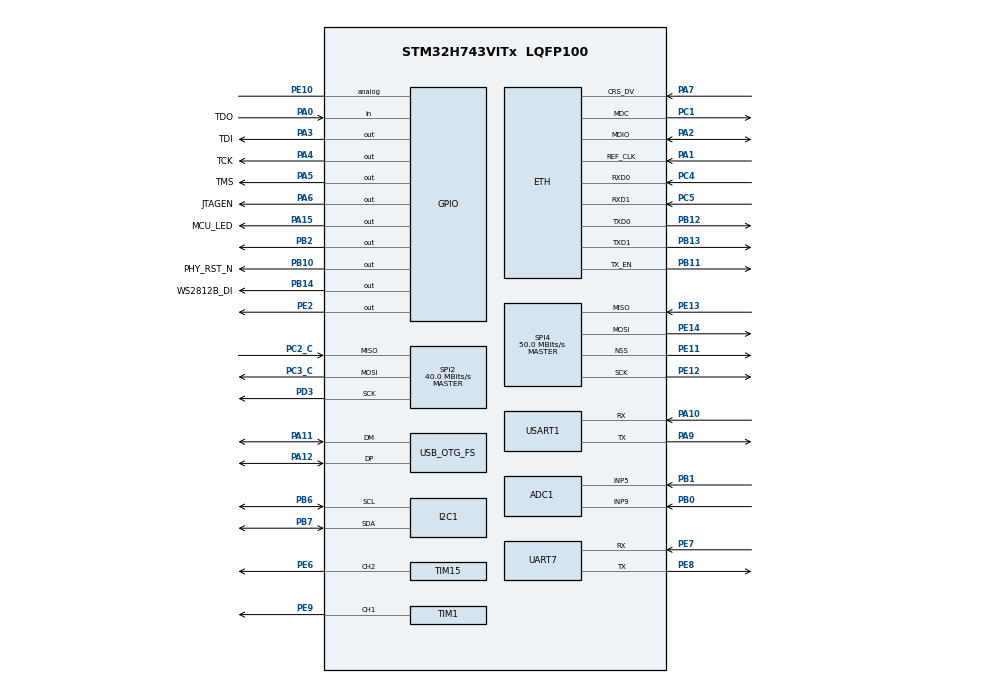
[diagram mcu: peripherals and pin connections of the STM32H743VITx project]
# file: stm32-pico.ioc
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ADC1.Channel-1\#ChannelRegularConversion=ADC_CHANNEL_5
ADC1.OversamplingMode=ENABLE
ADC1.Rank-1\#ChannelRegularConversion=1
ADC1.Ratio=10
ADC1.SamplingTime-1\#ChannelRegularConversion=ADC_SAMPLETIME_64CYCLES_5
ADC1.master=1
CORTEX_M7.AccessPermission-Cortex_Memory_Protection_Unit_Region0_Settings=MPU_REGION_FULL_ACCESS
CORTEX_M7.AccessPermission-Cortex_Memory_Protection_Unit_Region1_Settings=MPU_REGION_FULL_ACCESS
CORTEX_M7.BaseAddress-Cortex_Memory_Protection_Unit_Region0_Settings=0x30000000
CORTEX_M7.BaseAddress-Cortex_Memory_Protection_Unit_Region1_Settings=0x30000000
CORTEX_M7.CPU_DCache=Enabled
CORTEX_M7.CPU_ICache=Enabled
CORTEX_M7.DisableExec-Cortex_Memory_Protection_Unit_Region0_Settings=MPU_INSTRUCTION_ACCESS_DISABLE
CORTEX_M7.DisableExec-Cortex_Memory_Protection_Unit_Region1_Settings=MPU_INSTRUCTION_ACCESS_DISABLE
CORTEX_M7.Enable-Cortex_Memory_Protection_Unit_Region0_Settings=MPU_REGION_ENABLE
CORTEX_M7.Enable-Cortex_Memory_Protection_Unit_Region1_Settings=MPU_REGION_ENABLE
CORTEX_M7.IsBufferable-Cortex_Memory_Protection_Unit_Region1_Settings=MPU_ACCESS_BUFFERABLE
CORTEX_M7.IsShareable-Cortex_Memory_Protection_Unit_Region1_Settings=MPU_ACCESS_SHAREABLE
CORTEX_M7.MPU_Control=MPU_PRIVILEGED_DEFAULT
CORTEX_M7.Size-Cortex_Memory_Protection_Unit_Region0_Settings=MPU_REGION_SIZE_32KB
CORTEX_M7.Size-Cortex_Memory_Protection_Unit_Region1_Settings=MPU_REGION_SIZE_512B
CORTEX_M7.TypeExtField-Cortex_Memory_Protection_Unit_Region0_Settings=MPU_TEX_LEVEL1
ETH.MediaInterface=HAL_ETH_RMII_MODE
ETH.RxBuffLen=1536
ETH.RxDescAddress=0x30000000
ETH.TxDescAddress=0x30000060
FREERTOS.Tasks01=defaultTask,24,256,StartDefaultTask,Default,NULL,Dynamic,NULL,NULL
FREERTOS.configMINIMAL_STACK_SIZE=256
FREERTOS.configUSE_NEWLIB_REENTRANT=1
I2C1.Timing=0x10C0ECFF
IWDG1.Prescaler=IWDG_PRESCALER_32
LWIP.BSP.number=1
LWIP.DEFAULT_THREAD_PRIO=48
LWIP.GATEWAY_ADDRESS=192.168.031.001
LWIP.IP_ADDRESS=192.168.031.100
LWIP.LWIP_DHCP=0
LWIP.LWIP_RAM_HEAP_POINTER=0x30004000
LWIP.NETMASK_ADDRESS=255.255.255.000
LWIP.PBUF_POOL_BUFSIZE=1500
LWIP.TCP_MSS=1426
LWIP.TCP_WND=5704
LWIP.Version=v2.1.2_Cube
LWIP0.BSP.STBoard=false
LWIP0.BSP.api=BSP_COMPONENT_DRIVER
LWIP0.BSP.component=LAN8742
LWIP0.BSP.i2caddr=0
LWIP0.BSP.instance=LAN8742
LWIP0.BSP.name=Driver_PHY
LWIP0.BSP.solution=LAN8742
Mcu.Family=STM32H7
Mcu.Name=STM32H743VITx
Mcu.Package=LQFP100
NVIC.ETH_IRQn=true\:5\:0\:false\:false\:true\:true\:true\:true
NVIC.OTG_FS_IRQn=true\:5\:0\:false\:false\:true\:true\:true\:true
NVIC.PriorityGroup=NVIC_PRIORITYGROUP_4
NVIC.TIM2_IRQn=true\:15\:0\:false\:false\:true\:false\:false\:true
NVIC.TimeBase=TIM2_IRQn
NVIC.TimeBaseIP=TIM2
PA0.GPIO_Label=TDO
PA0.Signal=GPIO_Input
PA1.GPIO_Speed=GPIO_SPEED_FREQ_VERY_HIGH
PA1.Mode=RMII
PA1.Signal=ETH_REF_CLK
PA10.Mode=Asynchronous
PA10.Signal=USART1_RX
PA11.GPIO_Speed=GPIO_SPEED_FREQ_HIGH
PA11.Mode=Device_Only
PA11.Signal=USB_OTG_FS_DM
PA12.GPIO_Speed=GPIO_SPEED_FREQ_HIGH
PA12.Mode=Device_Only
PA12.Signal=USB_OTG_FS_DP
PA13\ (JTMS/SWDIO).Mode=Serial_Wire
PA13\ (JTMS/SWDIO).Signal=DEBUG_JTMS-SWDIO
PA14\ (JTCK/SWCLK).Mode=Serial_Wire
PA14\ (JTCK/SWCLK).Signal=DEBUG_JTCK-SWCLK
PA15\ (JTDI).GPIO_Label=MCU_LED
PA15\ (JTDI).Signal=GPIO_Output
PA2.GPIO_Speed=GPIO_SPEED_FREQ_VERY_HIGH
PA2.Mode=RMII
PA2.Signal=ETH_MDIO
PA3.GPIO_Label=TDI
PA3.GPIO_Speed=GPIO_SPEED_FREQ_HIGH
PA3.Signal=GPIO_Output
PA4.GPIO_Label=TCK
PA4.GPIO_Speed=GPIO_SPEED_FREQ_HIGH
PA4.Signal=GPIO_Output
PA5.GPIO_Label=TMS
PA5.Signal=GPIO_Output
PA6.GPIO_Label=JTAGEN
PA6.GPIO_Speed=GPIO_SPEED_FREQ_HIGH
PA6.Signal=GPIO_Output
PA7.GPIO_Speed=GPIO_SPEED_FREQ_VERY_HIGH
PA7.Mode=RMII
PA7.Signal=ETH_CRS_DV
PA9.Mode=Asynchronous
PA9.Signal=USART1_TX
PB0.Signal=ADCx_INP9
PB1.Signal=ADCx_INP5
PB10.GPIO_Label=PHY_RST_N
PB10.GPIO_PuPd=GPIO_PULLDOWN
PB10.Signal=GPIO_Output
PB11.GPIO_Speed=GPIO_SPEED_FREQ_VERY_HIGH
PB11.Mode=RMII
PB11.Signal=ETH_TX_EN
PB12.GPIO_Speed=GPIO_SPEED_FREQ_VERY_HIGH
PB12.Mode=RMII
PB12.Signal=ETH_TXD0
PB13.GPIO_Speed=GPIO_SPEED_FREQ_VERY_HIGH
PB13.Mode=RMII
PB13.Signal=ETH_TXD1
PB14.GPIO_Label=WS2812B_DI
PB14.GPIO_Speed=GPIO_SPEED_FREQ_HIGH
PB14.Signal=GPIO_Output
PB2.Signal=GPIO_Output
PB6.Mode=I2C
PB6.Signal=I2C1_SCL
PB7.Mode=I2C
PB7.Signal=I2C1_SDA
PC1.GPIO_Speed=GPIO_SPEED_FREQ_VERY_HIGH
PC1.Mode=RMII
PC1.Signal=ETH_MDC
PC2_C.Mode=Full_Duplex_Master
PC2_C.Signal=SPI2_MISO
PC3_C.Mode=Full_Duplex_Master
PC3_C.Signal=SPI2_MOSI
PC4.GPIO_Speed=GPIO_SPEED_FREQ_VERY_HIGH
PC4.Mode=RMII
PC4.Signal=ETH_RXD0
PC5.GPIO_Speed=GPIO_SPEED_FREQ_VERY_HIGH
PC5.Mode=RMII
PC5.Signal=ETH_RXD1
PD3.Mode=Full_Duplex_Master
PD3.Signal=SPI2_SCK
PE10.Signal=GPIO_Analog
PE11.Mode=NSS_Signal_Hard_Output
PE11.Signal=SPI4_NSS
PE12.Mode=Full_Duplex_Master
PE12.Signal=SPI4_SCK
PE13.Mode=Full_Duplex_Master
PE13.Signal=SPI4_MISO
PE14.Mode=Full_Duplex_Master
PE14.Signal=SPI4_MOSI
PE2.Signal=GPIO_Output
PE6.Signal=S_TIM15_CH2
PE7.Mode=Asynchronous
PE7.Signal=UART7_RX
PE8.Mode=Asynchronous
PE8.Signal=UART7_TX
PE9.Signal=S_TIM1_CH1
PH0-OSC_IN\ (PH0).Mode=HSE-External-Oscillator
PH0-OSC_IN\ (PH0).Signal=RCC_OSC_IN
PH1-OSC_OUT\ (PH1).Mode=HSE-External-Oscillator
PH1-OSC_OUT\ (PH1).Signal=RCC_OSC_OUT
ProjectManager.HeapSize=0x200
ProjectManager.StackSize=0x400
ProjectManager.TargetToolchain=STM32CubeIDE
RCC.ADCFreq_Value=80000000
RCC.APB1Freq_Value=100000000
RCC.APB2Freq_Value=100000000
RCC.APB3Freq_Value=100000000
RCC.APB4Freq_Value=100000000
RCC.CortexFreq_Value=400000000
RCC.D1PPRE=RCC_APB3_DIV2
RCC.D2PPRE1=RCC_APB1_DIV2
RCC.D2PPRE2=RCC_APB2_DIV2
RCC.D3PPRE=RCC_APB4_DIV2
RCC.DIVM1=2
RCC.DIVM2=2
RCC.DIVN1=50
RCC.DIVN2=50
RCC.DIVP2=10
RCC.DIVQ1=10
RCC.HCLKFreq_Value=200000000
RCC.HPRE=RCC_HCLK_DIV2
RCC.HSIDiv=RCC_PLLSAIDIVR_2
RCC.PLLSourceVirtual=RCC_PLLSOURCE_HSI
RCC.SYSCLKFreq_VALUE=400000000
RCC.SYSCLKSource=RCC_SYSCLKSOURCE_PLLCLK
RCC.USBCLockSelection=RCC_USBCLKSOURCE_HSI48
RCC.USBFreq_Value=48000000
SH.ADCx_INP5.0=ADC1_INP5,IN5-Single-Ended
SH.ADCx_INP9.0=ADC1_INP9,IN9-Single-Ended
SH.S_TIM15_CH2.0=TIM15_CH2,PWM Generation2 CH2
SH.S_TIM1_CH1.0=TIM1_CH1,PWM Generation1 CH1
SPI2.BaudRatePrescaler=SPI_BAUDRATEPRESCALER_2
SPI2.CalculateBaudRate=40.0 MBits/s
SPI2.Direction=SPI_DIRECTION_2LINES
SPI2.Mode=SPI_MODE_MASTER
SPI2.VirtualType=VM_MASTER
SPI4.CalculateBaudRate=50.0 MBits/s
SPI4.Direction=SPI_DIRECTION_2LINES
SPI4.Mode=SPI_MODE_MASTER
SPI4.VirtualNSS=VM_NSSHARD
SPI4.VirtualType=VM_MASTER
TIM1.Channel-PWM\ Generation1\ CH1=TIM_CHANNEL_1
TIM15.Channel-PWM\ Generation2\ CH2=TIM_CHANNEL_2
USART1.VirtualMode-Asynchronous=VM_ASYNC
USB_OTG_FS.VirtualMode=Device_Only
VP_FREERTOS_VS_CMSIS_V2.Mode=CMSIS_V2
VP_IWDG1_VS_IWDG.Mode=IWDG_Activate
VP_LWIP_VS_Enabled.Mode=Enabled
VP_SYS_VS_tim2.Mode=TIM2
VP_TIM1_VS_ClockSourceINT.Mode=Internal
VP_TIM1_VS_ClockSourceITR.Mode=TriggerSource_ITR0
VP_TIM1_VS_ControllerModeReset.Mode=Reset Mode
VREF+.Mode=InternalMode
VREF+.Signal=VREFBUF_OUT
VREFBUF.VoltageScaling=SYSCFG_VREFBUF_VOLTAGE_SCALE1
board=custom

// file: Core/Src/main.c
/* USER CODE BEGIN Header */
/**
  ******************************************************************************
  * @file           : main.c
  * @brief          : Main program body
  ******************************************************************************
  * @attention
  *
  * Copyright (c) 2024 STMicroelectronics.
  * All rights reserved.
  *
  * This software is licensed under terms that can be found in the LICENSE file
  * in the root directory of this software component.
  * If no LICENSE file comes with this software, it is provided AS-IS.
  *
  ******************************************************************************
  */

/**
 * Sector 0     0x08000000-0x0801FFFF Boot 128KB
 * Sector 1     0x08020000-0x0803FFFF Boot Address, 4B
 * Sector 2-7   0x08040000-0x080FFFFF APP1 768KB
 * Sector 8-3   0x08100000-0x081BFFFF APP2 768KB
 * Sector 14-15 0x081C0000-0x081FFFFF Data 256KB
 */
/* USER CODE END Header */
#include "main.h"
#include "cmsis_os.h"
#include "lwip.h"

/* USER CODE BEGIN Includes */
#include <ctype.h>
#include "bsp/board_api.h"
#include "tusb.h"
#include "usb_stdio.h"
#include "console.h"
#include "pico_cli.h"
#include "pico_reg.h"
/* USER CODE END Includes */

ADC_HandleTypeDef hadc1;

I2C_HandleTypeDef hi2c1;

IWDG_HandleTypeDef hiwdg1;

SPI_HandleTypeDef hspi2;
SPI_HandleTypeDef hspi4;

TIM_HandleTypeDef htim1;
TIM_HandleTypeDef htim15;

UART_HandleTypeDef huart7;
UART_HandleTypeDef huart1;

PCD_HandleTypeDef hpcd_USB_OTG_FS;

/* Definitions for defaultTask */
osThreadId_t defaultTaskHandle;
const osThreadAttr_t defaultTask_attributes = {
  .name = "defaultTask",
  .stack_size = 256 * 4,
  .priority = (osPriority_t) osPriorityNormal,
};
/* USER CODE BEGIN PV */
static int g_heat_led_gap = 500;

osThreadId_t usbTaskHandle;
const osThreadAttr_t usbTask_attributes = {
  .name = "usbTask",
  .stack_size = 256 * 4,
  .priority = (osPriority_t) osPriorityRealtime,
};

osThreadId_t cliTaskHandle;
const osThreadAttr_t cliTask_attributes = {
  .name = "cliTask",
  .stack_size = 256 * 4,
  .priority = (osPriority_t) osPriorityNormal,
};

osThreadId_t iwdgTaskHandle;
const osThreadAttr_t iwdgTask_attributes = {
  .name = "iwdgTask",
  .stack_size = 256,
  .priority = (osPriority_t) osPriorityNormal,
};

uint64_t get_tick_ms()
{
  return (uint64_t)HAL_GetTick();
}

/* USER CODE END PV */

void SystemClock_Config(void);
static void MPU_Config(void);
static void MX_GPIO_Init(void);
static void MX_USB_OTG_FS_PCD_Init(void);
static void MX_SPI2_Init(void);
static void MX_I2C1_Init(void);
static void MX_UART7_Init(void);
static void MX_USART1_UART_Init(void);
static void MX_ADC1_Init(void);
static void MX_TIM1_Init(void);
static void MX_TIM15_Init(void);
static void MX_IWDG1_Init(void);
static void MX_SPI4_Init(void);
void StartDefaultTask(void *argument);

/* USER CODE BEGIN PFP */
typedef void (*pApp)(void);
/* USER CODE END PFP */

/* USER CODE BEGIN 0 */
uint32_t CODE_START_ADDRESS = FLASH_START_ADDRESS;

/**
 * 关于IWDG
 * 使用LSI作为时钟源，LSI是32KHz
 */

/* USER CODE END 0 */

int main(void)
{
  /* USER CODE BEGIN 1 */
  // const uint32_t bootflag = 0x12345678;
  // uint32_t ptr = (uint32_t)(&bootflag);
  // if (ptr < APP_BOOT_ADDRESS_PHY_ADDR) {
  //   CODE_START_ADDRESS = FLASH_START_ADDRESS;
  // }
  // if (ptr > APP1_SECTOR_ADDRESS && ptr < APP2_SECTOR_ADDRESS) {
  //   CODE_START_ADDRESS = APP1_SECTOR_ADDRESS;
  //   SCB->VTOR = APP1_SECTOR_ADDRESS;
  // }
  // if (ptr > APP2_SECTOR_ADDRESS && ptr < DATA_SECTOR_ADDRESS) {
  //   CODE_START_ADDRESS = APP2_SECTOR_ADDRESS;
  //   SCB->VTOR = APP2_SECTOR_ADDRESS;
  // }
  // if (CODE_START_ADDRESS == FLASH_START_ADDRESS) { // bootloader app
  //   const uint32_t APPLICATION_ADDRESS = (*(__IO uint32_t *)APP_BOOT_ADDRESS_PHY_ADDR);
  //   if (APPLICATION_ADDRESS == APP1_SECTOR_ADDRESS || APPLICATION_ADDRESS == APP2_SECTOR_ADDRESS) {
  //     const uint32_t JumpAddress = *(__IO uint32_t *)(APPLICATION_ADDRESS + 4);
  //     pApp JumpToApp = (pApp)JumpAddress;
  //     /* Reconfigure vector table offset register to match the application location */
  //     SCB->VTOR = JumpAddress;
  //     /* Initialize user application's Stack Pointer */
  //     __set_MSP(*(__IO uint32_t *)APPLICATION_ADDRESS);

  //     JumpToApp();
  //     while (1)
  //       ;
  //   }
  // }
  SCB->VTOR = APP1_SECTOR_ADDRESS;
  /* USER CODE END 1 */

  /* MPU Configuration--------------------------------------------------------*/
  MPU_Config();

  /* Enable I-Cache---------------------------------------------------------*/
  SCB_EnableICache();

  /* Enable D-Cache---------------------------------------------------------*/
  SCB_EnableDCache();

  /* MCU Configuration--------------------------------------------------------*/

  /* Reset of all peripherals, Initializes the Flash interface and the Systick. */
  HAL_Init();

  /* Configure the system clock */
  SystemClock_Config();

  /* Initialize all configured peripherals */
  MX_GPIO_Init();
  MX_USB_OTG_FS_PCD_Init();
  MX_SPI2_Init();
  MX_I2C1_Init();
  MX_UART7_Init();
  MX_USART1_UART_Init();
  MX_ADC1_Init();
  MX_TIM1_Init();
  MX_TIM15_Init();
  MX_IWDG1_Init();
  MX_SPI4_Init();
  /* USER CODE BEGIN 2 */
  HAL_Delay(1);
  HAL_GPIO_WritePin(PHY_RST_N_GPIO_Port, PHY_RST_N_Pin, GPIO_PIN_SET);

  HAL_ADCEx_Calibration_Start(&hadc1, ADC_CALIB_OFFSET, ADC_SINGLE_ENDED);

  /* USER CODE END 2 */

  /* Init scheduler */
  osKernelInitialize();

  /* Create the thread(s) */
  /* creation of defaultTask */
  defaultTaskHandle = osThreadNew(StartDefaultTask, NULL, &defaultTask_attributes);

  /* Start scheduler */
  osKernelStart();

  /* We should never get here as control is now taken by the scheduler */
  /* Infinite loop */
  while (1)
  {

  }
}

void SystemClock_Config(void)
{
  RCC_OscInitTypeDef RCC_OscInitStruct = {0};
  RCC_ClkInitTypeDef RCC_ClkInitStruct = {0};

  /** Supply configuration update enable
  */
  HAL_PWREx_ConfigSupply(PWR_LDO_SUPPLY);
  /** Configure the main internal regulator output voltage
  */
  __HAL_PWR_VOLTAGESCALING_CONFIG(PWR_REGULATOR_VOLTAGE_SCALE1);

  while(!__HAL_PWR_GET_FLAG(PWR_FLAG_VOSRDY)) {}
  /** Macro to configure the PLL clock source
  */
  __HAL_RCC_PLL_PLLSOURCE_CONFIG(RCC_PLLSOURCE_HSI);
  /** Initializes the RCC Oscillators according to the specified parameters
  * in the RCC_OscInitTypeDef structure.
  */
  RCC_OscInitStruct.OscillatorType = RCC_OSCILLATORTYPE_HSI48|RCC_OSCILLATORTYPE_HSI
                              |RCC_OSCILLATORTYPE_LSI;
  RCC_OscInitStruct.HSIState = RCC_HSI_DIV2;
  RCC_OscInitStruct.HSICalibrationValue = RCC_HSICALIBRATION_DEFAULT;
  RCC_OscInitStruct.LSIState = RCC_LSI_ON;
  RCC_OscInitStruct.HSI48State = RCC_HSI48_ON;
  RCC_OscInitStruct.PLL.PLLState = RCC_PLL_ON;
  RCC_OscInitStruct.PLL.PLLSource = RCC_PLLSOURCE_HSI;
  RCC_OscInitStruct.PLL.PLLM = 2;
  RCC_OscInitStruct.PLL.PLLN = 50;
  RCC_OscInitStruct.PLL.PLLP = 2;
  RCC_OscInitStruct.PLL.PLLQ = 10;
  RCC_OscInitStruct.PLL.PLLR = 2;
  RCC_OscInitStruct.PLL.PLLRGE = RCC_PLL1VCIRANGE_3;
  RCC_OscInitStruct.PLL.PLLVCOSEL = RCC_PLL1VCOWIDE;
  RCC_OscInitStruct.PLL.PLLFRACN = 0;
  if (HAL_RCC_OscConfig(&RCC_OscInitStruct) != HAL_OK)
  {
    Error_Handler();
  }
  /** Initializes the CPU, AHB and APB buses clocks
  */
  RCC_ClkInitStruct.ClockType = RCC_CLOCKTYPE_HCLK|RCC_CLOCKTYPE_SYSCLK
                              |RCC_CLOCKTYPE_PCLK1|RCC_CLOCKTYPE_PCLK2
                              |RCC_CLOCKTYPE_D3PCLK1|RCC_CLOCKTYPE_D1PCLK1;
  RCC_ClkInitStruct.SYSCLKSource = RCC_SYSCLKSOURCE_PLLCLK;
  RCC_ClkInitStruct.SYSCLKDivider = RCC_SYSCLK_DIV1;
  RCC_ClkInitStruct.AHBCLKDivider = RCC_HCLK_DIV2;
  RCC_ClkInitStruct.APB3CLKDivider = RCC_APB3_DIV2;
  RCC_ClkInitStruct.APB1CLKDivider = RCC_APB1_DIV2;
  RCC_ClkInitStruct.APB2CLKDivider = RCC_APB2_DIV2;
  RCC_ClkInitStruct.APB4CLKDivider = RCC_APB4_DIV2;

  if (HAL_RCC_ClockConfig(&RCC_ClkInitStruct, FLASH_LATENCY_2) != HAL_OK)
  {
    Error_Handler();
  }
}

static void MX_ADC1_Init(void)
{

  ADC_MultiModeTypeDef multimode = {0};
  ADC_ChannelConfTypeDef sConfig = {0};

  /** Common config
  */
  hadc1.Instance = ADC1;
  hadc1.Init.ClockPrescaler = ADC_CLOCK_ASYNC_DIV4;
  hadc1.Init.Resolution = ADC_RESOLUTION_16B;
  hadc1.Init.ScanConvMode = ADC_SCAN_DISABLE;
  hadc1.Init.EOCSelection = ADC_EOC_SINGLE_CONV;
  hadc1.Init.LowPowerAutoWait = DISABLE;
  hadc1.Init.ContinuousConvMode = DISABLE;
  hadc1.Init.NbrOfConversion = 1;
  hadc1.Init.DiscontinuousConvMode = DISABLE;
  hadc1.Init.ExternalTrigConv = ADC_SOFTWARE_START;
  hadc1.Init.ExternalTrigConvEdge = ADC_EXTERNALTRIGCONVEDGE_NONE;
  hadc1.Init.ConversionDataManagement = ADC_CONVERSIONDATA_DR;
  hadc1.Init.Overrun = ADC_OVR_DATA_PRESERVED;
  hadc1.Init.LeftBitShift = ADC_LEFTBITSHIFT_NONE;
  hadc1.Init.OversamplingMode = ENABLE;
  hadc1.Init.Oversampling.Ratio = 10;
  hadc1.Init.Oversampling.RightBitShift = ADC_RIGHTBITSHIFT_NONE;
  hadc1.Init.Oversampling.TriggeredMode = ADC_TRIGGEREDMODE_SINGLE_TRIGGER;
  hadc1.Init.Oversampling.OversamplingStopReset = ADC_REGOVERSAMPLING_CONTINUED_MODE;
  if (HAL_ADC_Init(&hadc1) != HAL_OK)
  {
    Error_Handler();
  }
  /** Configure the ADC multi-mode
  */
  multimode.Mode = ADC_MODE_INDEPENDENT;
  if (HAL_ADCEx_MultiModeConfigChannel(&hadc1, &multimode) != HAL_OK)
  {
    Error_Handler();
  }
  /** Configure Regular Channel
  */
  sConfig.Channel = ADC_CHANNEL_5;
  sConfig.Rank = ADC_REGULAR_RANK_1;
  sConfig.SamplingTime = ADC_SAMPLETIME_64CYCLES_5;
  sConfig.SingleDiff = ADC_SINGLE_ENDED;
  sConfig.OffsetNumber = ADC_OFFSET_NONE;
  sConfig.Offset = 0;
  sConfig.OffsetSignedSaturation = DISABLE;
  if (HAL_ADC_ConfigChannel(&hadc1, &sConfig) != HAL_OK)
  {
    Error_Handler();
  }

}

static void MX_I2C1_Init(void)
{

  hi2c1.Instance = I2C1;
  hi2c1.Init.Timing = 0x10C0ECFF;
  hi2c1.Init.OwnAddress1 = 0;
  hi2c1.Init.AddressingMode = I2C_ADDRESSINGMODE_7BIT;
  hi2c1.Init.DualAddressMode = I2C_DUALADDRESS_DISABLE;
  hi2c1.Init.OwnAddress2 = 0;
  hi2c1.Init.OwnAddress2Masks = I2C_OA2_NOMASK;
  hi2c1.Init.GeneralCallMode = I2C_GENERALCALL_DISABLE;
  hi2c1.Init.NoStretchMode = I2C_NOSTRETCH_DISABLE;
  if (HAL_I2C_Init(&hi2c1) != HAL_OK)
  {
    Error_Handler();
  }
  /** Configure Analogue filter
  */
  if (HAL_I2CEx_ConfigAnalogFilter(&hi2c1, I2C_ANALOGFILTER_ENABLE) != HAL_OK)
  {
    Error_Handler();
  }
  /** Configure Digital filter
  */
  if (HAL_I2CEx_ConfigDigitalFilter(&hi2c1, 0) != HAL_OK)
  {
    Error_Handler();
  }

}

static void MX_IWDG1_Init(void)
{

  hiwdg1.Instance = IWDG1;
  hiwdg1.Init.Prescaler = IWDG_PRESCALER_32;
  hiwdg1.Init.Window = 4095;
  hiwdg1.Init.Reload = 4095;
  if (HAL_IWDG_Init(&hiwdg1) != HAL_OK)
  {
    Error_Handler();
  }

}

static void MX_SPI2_Init(void)
{

  /* SPI2 parameter configuration*/
  hspi2.Instance = SPI2;
  hspi2.Init.Mode = SPI_MODE_MASTER;
  hspi2.Init.Direction = SPI_DIRECTION_2LINES;
  hspi2.Init.DataSize = SPI_DATASIZE_4BIT;
  hspi2.Init.CLKPolarity = SPI_POLARITY_LOW;
  hspi2.Init.CLKPhase = SPI_PHASE_1EDGE;
  hspi2.Init.NSS = SPI_NSS_SOFT;
  hspi2.Init.BaudRatePrescaler = SPI_BAUDRATEPRESCALER_2;
  hspi2.Init.FirstBit = SPI_FIRSTBIT_MSB;
  hspi2.Init.TIMode = SPI_TIMODE_DISABLE;
  hspi2.Init.CRCCalculation = SPI_CRCCALCULATION_DISABLE;
  hspi2.Init.CRCPolynomial = 0x0;
  hspi2.Init.NSSPMode = SPI_NSS_PULSE_ENABLE;
  hspi2.Init.NSSPolarity = SPI_NSS_POLARITY_LOW;
  hspi2.Init.FifoThreshold = SPI_FIFO_THRESHOLD_01DATA;
  hspi2.Init.TxCRCInitializationPattern = SPI_CRC_INITIALIZATION_ALL_ZERO_PATTERN;
  hspi2.Init.RxCRCInitializationPattern = SPI_CRC_INITIALIZATION_ALL_ZERO_PATTERN;
  hspi2.Init.MasterSSIdleness = SPI_MASTER_SS_IDLENESS_00CYCLE;
  hspi2.Init.MasterInterDataIdleness = SPI_MASTER_INTERDATA_IDLENESS_00CYCLE;
  hspi2.Init.MasterReceiverAutoSusp = SPI_MASTER_RX_AUTOSUSP_DISABLE;
  hspi2.Init.MasterKeepIOState = SPI_MASTER_KEEP_IO_STATE_DISABLE;
  hspi2.Init.IOSwap = SPI_IO_SWAP_DISABLE;
  if (HAL_SPI_Init(&hspi2) != HAL_OK)
  {
    Error_Handler();
  }

}

static void MX_SPI4_Init(void)
{

  /* SPI4 parameter configuration*/
  hspi4.Instance = SPI4;
  hspi4.Init.Mode = SPI_MODE_MASTER;
  hspi4.Init.Direction = SPI_DIRECTION_2LINES;
  hspi4.Init.DataSize = SPI_DATASIZE_4BIT;
  hspi4.Init.CLKPolarity = SPI_POLARITY_LOW;
  hspi4.Init.CLKPhase = SPI_PHASE_1EDGE;
  hspi4.Init.NSS = SPI_NSS_HARD_OUTPUT;
  hspi4.Init.BaudRatePrescaler = SPI_BAUDRATEPRESCALER_2;
  hspi4.Init.FirstBit = SPI_FIRSTBIT_MSB;
  hspi4.Init.TIMode = SPI_TIMODE_DISABLE;
  hspi4.Init.CRCCalculation = SPI_CRCCALCULATION_DISABLE;
  hspi4.Init.CRCPolynomial = 0x0;
  hspi4.Init.NSSPMode = SPI_NSS_PULSE_ENABLE;
  hspi4.Init.NSSPolarity = SPI_NSS_POLARITY_LOW;
  hspi4.Init.FifoThreshold = SPI_FIFO_THRESHOLD_01DATA;
  hspi4.Init.TxCRCInitializationPattern = SPI_CRC_INITIALIZATION_ALL_ZERO_PATTERN;
  hspi4.Init.RxCRCInitializationPattern = SPI_CRC_INITIALIZATION_ALL_ZERO_PATTERN;
  hspi4.Init.MasterSSIdleness = SPI_MASTER_SS_IDLENESS_00CYCLE;
  hspi4.Init.MasterInterDataIdleness = SPI_MASTER_INTERDATA_IDLENESS_00CYCLE;
  hspi4.Init.MasterReceiverAutoSusp = SPI_MASTER_RX_AUTOSUSP_DISABLE;
  hspi4.Init.MasterKeepIOState = SPI_MASTER_KEEP_IO_STATE_DISABLE;
  hspi4.Init.IOSwap = SPI_IO_SWAP_DISABLE;
  if (HAL_SPI_Init(&hspi4) != HAL_OK)
  {
    Error_Handler();
  }

}

static void MX_TIM1_Init(void)
{

  TIM_ClockConfigTypeDef sClockSourceConfig = {0};
  TIM_SlaveConfigTypeDef sSlaveConfig = {0};
  TIM_MasterConfigTypeDef sMasterConfig = {0};
  TIM_OC_InitTypeDef sConfigOC = {0};
  TIM_BreakDeadTimeConfigTypeDef sBreakDeadTimeConfig = {0};

  htim1.Instance = TIM1;
  htim1.Init.Prescaler = 0;
  htim1.Init.CounterMode = TIM_COUNTERMODE_UP;
  htim1.Init.Period = 65535;
  htim1.Init.ClockDivision = TIM_CLOCKDIVISION_DIV1;
  htim1.Init.RepetitionCounter = 0;
  htim1.Init.AutoReloadPreload = TIM_AUTORELOAD_PRELOAD_DISABLE;
  if (HAL_TIM_Base_Init(&htim1) != HAL_OK)
  {
    Error_Handler();
  }
  sClockSourceConfig.ClockSource = TIM_CLOCKSOURCE_INTERNAL;
  if (HAL_TIM_ConfigClockSource(&htim1, &sClockSourceConfig) != HAL_OK)
  {
    Error_Handler();
  }
  if (HAL_TIM_PWM_Init(&htim1) != HAL_OK)
  {
    Error_Handler();
  }
  sSlaveConfig.SlaveMode = TIM_SLAVEMODE_RESET;
  sSlaveConfig.InputTrigger = TIM_TS_ITR0;
  if (HAL_TIM_SlaveConfigSynchro(&htim1, &sSlaveConfig) != HAL_OK)
  {
    Error_Handler();
  }
  sMasterConfig.MasterOutputTrigger = TIM_TRGO_RESET;
  sMasterConfig.MasterOutputTrigger2 = TIM_TRGO2_RESET;
  sMasterConfig.MasterSlaveMode = TIM_MASTERSLAVEMODE_DISABLE;
  if (HAL_TIMEx_MasterConfigSynchronization(&htim1, &sMasterConfig) != HAL_OK)
  {
    Error_Handler();
  }
  sConfigOC.OCMode = TIM_OCMODE_PWM1;
  sConfigOC.Pulse = 0;
  sConfigOC.OCPolarity = TIM_OCPOLARITY_HIGH;
  sConfigOC.OCNPolarity = TIM_OCNPOLARITY_HIGH;
  sConfigOC.OCFastMode = TIM_OCFAST_DISABLE;
  sConfigOC.OCIdleState = TIM_OCIDLESTATE_RESET;
  sConfigOC.OCNIdleState = TIM_OCNIDLESTATE_RESET;
  if (HAL_TIM_PWM_ConfigChannel(&htim1, &sConfigOC, TIM_CHANNEL_1) != HAL_OK)
  {
    Error_Handler();
  }
  sBreakDeadTimeConfig.OffStateRunMode = TIM_OSSR_DISABLE;
  sBreakDeadTimeConfig.OffStateIDLEMode = TIM_OSSI_DISABLE;
  sBreakDeadTimeConfig.LockLevel = TIM_LOCKLEVEL_OFF;
  sBreakDeadTimeConfig.DeadTime = 0;
  sBreakDeadTimeConfig.BreakState = TIM_BREAK_DISABLE;
  sBreakDeadTimeConfig.BreakPolarity = TIM_BREAKPOLARITY_HIGH;
  sBreakDeadTimeConfig.BreakFilter = 0;
  sBreakDeadTimeConfig.Break2State = TIM_BREAK2_DISABLE;
  sBreakDeadTimeConfig.Break2Polarity = TIM_BREAK2POLARITY_HIGH;
  sBreakDeadTimeConfig.Break2Filter = 0;
  sBreakDeadTimeConfig.AutomaticOutput = TIM_AUTOMATICOUTPUT_DISABLE;
  if (HAL_TIMEx_ConfigBreakDeadTime(&htim1, &sBreakDeadTimeConfig) != HAL_OK)
  {
    Error_Handler();
  }
  HAL_TIM_MspPostInit(&htim1);

}

static void MX_TIM15_Init(void)
{

  TIM_MasterConfigTypeDef sMasterConfig = {0};
  TIM_OC_InitTypeDef sConfigOC = {0};
  TIM_BreakDeadTimeConfigTypeDef sBreakDeadTimeConfig = {0};

  htim15.Instance = TIM15;
  htim15.Init.Prescaler = 0;
  htim15.Init.CounterMode = TIM_COUNTERMODE_UP;
  htim15.Init.Period = 65535;
  htim15.Init.ClockDivision = TIM_CLOCKDIVISION_DIV1;
  htim15.Init.RepetitionCounter = 0;
  htim15.Init.AutoReloadPreload = TIM_AUTORELOAD_PRELOAD_DISABLE;
  if (HAL_TIM_PWM_Init(&htim15) != HAL_OK)
  {
    Error_Handler();
  }
  sMasterConfig.MasterOutputTrigger = TIM_TRGO_RESET;
  sMasterConfig.MasterSlaveMode = TIM_MASTERSLAVEMODE_DISABLE;
  if (HAL_TIMEx_MasterConfigSynchronization(&htim15, &sMasterConfig) != HAL_OK)
  {
    Error_Handler();
  }
  sConfigOC.OCMode = TIM_OCMODE_PWM1;
  sConfigOC.Pulse = 0;
  sConfigOC.OCPolarity = TIM_OCPOLARITY_HIGH;
  sConfigOC.OCNPolarity = TIM_OCNPOLARITY_HIGH;
  sConfigOC.OCFastMode = TIM_OCFAST_DISABLE;
  sConfigOC.OCIdleState = TIM_OCIDLESTATE_RESET;
  sConfigOC.OCNIdleState = TIM_OCNIDLESTATE_RESET;
  if (HAL_TIM_PWM_ConfigChannel(&htim15, &sConfigOC, TIM_CHANNEL_2) != HAL_OK)
  {
    Error_Handler();
  }
  sBreakDeadTimeConfig.OffStateRunMode = TIM_OSSR_DISABLE;
  sBreakDeadTimeConfig.OffStateIDLEMode = TIM_OSSI_DISABLE;
  sBreakDeadTimeConfig.LockLevel = TIM_LOCKLEVEL_OFF;
  sBreakDeadTimeConfig.DeadTime = 0;
  sBreakDeadTimeConfig.BreakState = TIM_BREAK_DISABLE;
  sBreakDeadTimeConfig.BreakPolarity = TIM_BREAKPOLARITY_HIGH;
  sBreakDeadTimeConfig.BreakFilter = 0;
  sBreakDeadTimeConfig.AutomaticOutput = TIM_AUTOMATICOUTPUT_DISABLE;
  if (HAL_TIMEx_ConfigBreakDeadTime(&htim15, &sBreakDeadTimeConfig) != HAL_OK)
  {
    Error_Handler();
  }
  HAL_TIM_MspPostInit(&htim15);

}

static void MX_UART7_Init(void)
{

  huart7.Instance = UART7;
  huart7.Init.BaudRate = 115200;
  huart7.Init.WordLength = UART_WORDLENGTH_8B;
  huart7.Init.StopBits = UART_STOPBITS_1;
  huart7.Init.Parity = UART_PARITY_NONE;
  huart7.Init.Mode = UART_MODE_TX_RX;
  huart7.Init.HwFlowCtl = UART_HWCONTROL_NONE;
  huart7.Init.OverSampling = UART_OVERSAMPLING_16;
  huart7.Init.OneBitSampling = UART_ONE_BIT_SAMPLE_DISABLE;
  huart7.Init.ClockPrescaler = UART_PRESCALER_DIV1;
  huart7.AdvancedInit.AdvFeatureInit = UART_ADVFEATURE_NO_INIT;
  if (HAL_UART_Init(&huart7) != HAL_OK)
  {
    Error_Handler();
  }
  if (HAL_UARTEx_SetTxFifoThreshold(&huart7, UART_TXFIFO_THRESHOLD_1_8) != HAL_OK)
  {
    Error_Handler();
  }
  if (HAL_UARTEx_SetRxFifoThreshold(&huart7, UART_RXFIFO_THRESHOLD_1_8) != HAL_OK)
  {
    Error_Handler();
  }
  if (HAL_UARTEx_DisableFifoMode(&huart7) != HAL_OK)
  {
    Error_Handler();
  }

}

static void MX_USART1_UART_Init(void)
{

  huart1.Instance = USART1;
  huart1.Init.BaudRate = 115200;
  huart1.Init.WordLength = UART_WORDLENGTH_8B;
  huart1.Init.StopBits = UART_STOPBITS_1;
  huart1.Init.Parity = UART_PARITY_NONE;
  huart1.Init.Mode = UART_MODE_TX_RX;
  huart1.Init.HwFlowCtl = UART_HWCONTROL_NONE;
  huart1.Init.OverSampling = UART_OVERSAMPLING_16;
  huart1.Init.OneBitSampling = UART_ONE_BIT_SAMPLE_DISABLE;
  huart1.Init.ClockPrescaler = UART_PRESCALER_DIV1;
  huart1.AdvancedInit.AdvFeatureInit = UART_ADVFEATURE_NO_INIT;
  if (HAL_UART_Init(&huart1) != HAL_OK)
  {
    Error_Handler();
  }
  if (HAL_UARTEx_SetTxFifoThreshold(&huart1, UART_TXFIFO_THRESHOLD_1_8) != HAL_OK)
  {
    Error_Handler();
  }
  if (HAL_UARTEx_SetRxFifoThreshold(&huart1, UART_RXFIFO_THRESHOLD_1_8) != HAL_OK)
  {
    Error_Handler();
  }
  if (HAL_UARTEx_DisableFifoMode(&huart1) != HAL_OK)
  {
    Error_Handler();
  }

}

static void MX_USB_OTG_FS_PCD_Init(void)
{

  hpcd_USB_OTG_FS.Instance = USB_OTG_FS;
  hpcd_USB_OTG_FS.Init.dev_endpoints = 9;
  hpcd_USB_OTG_FS.Init.speed = PCD_SPEED_FULL;
  hpcd_USB_OTG_FS.Init.dma_enable = DISABLE;
  hpcd_USB_OTG_FS.Init.phy_itface = PCD_PHY_EMBEDDED;
  hpcd_USB_OTG_FS.Init.Sof_enable = DISABLE;
  hpcd_USB_OTG_FS.Init.low_power_enable = DISABLE;
  hpcd_USB_OTG_FS.Init.lpm_enable = DISABLE;
  hpcd_USB_OTG_FS.Init.battery_charging_enable = DISABLE;
  hpcd_USB_OTG_FS.Init.vbus_sensing_enable = DISABLE;
  hpcd_USB_OTG_FS.Init.use_dedicated_ep1 = DISABLE;
  if (HAL_PCD_Init(&hpcd_USB_OTG_FS) != HAL_OK)
  {
    Error_Handler();
  }

}

static void MX_GPIO_Init(void)
{
  GPIO_InitTypeDef GPIO_InitStruct = {0};

  /* GPIO Ports Clock Enable */
  __HAL_RCC_GPIOE_CLK_ENABLE();
  __HAL_RCC_GPIOH_CLK_ENABLE();
  __HAL_RCC_GPIOC_CLK_ENABLE();
  __HAL_RCC_GPIOA_CLK_ENABLE();
  __HAL_RCC_GPIOB_CLK_ENABLE();
  __HAL_RCC_GPIOD_CLK_ENABLE();

  /*Configure GPIO pin Output Level */
  HAL_GPIO_WritePin(GPIOE, GPIO_PIN_2, GPIO_PIN_RESET);

  /*Configure GPIO pin Output Level */
  HAL_GPIO_WritePin(GPIOA, TDI_Pin|TCK_Pin|TMS_Pin|JTAGEN_Pin
                          |MCU_LED_Pin, GPIO_PIN_RESET);

  /*Configure GPIO pin Output Level */
  HAL_GPIO_WritePin(GPIOB, GPIO_PIN_2|PHY_RST_N_Pin|WS2812B_DI_Pin, GPIO_PIN_RESET);

  /*Configure GPIO pin : PE2 */
  GPIO_InitStruct.Pin = GPIO_PIN_2;
  GPIO_InitStruct.Mode = GPIO_MODE_OUTPUT_PP;
  GPIO_InitStruct.Pull = GPIO_NOPULL;
  GPIO_InitStruct.Speed = GPIO_SPEED_FREQ_LOW;
  HAL_GPIO_Init(GPIOE, &GPIO_InitStruct);

  /*Configure GPIO pin : TDO_Pin */
  GPIO_InitStruct.Pin = TDO_Pin;
  GPIO_InitStruct.Mode = GPIO_MODE_INPUT;
  GPIO_InitStruct.Pull = GPIO_NOPULL;
  HAL_GPIO_Init(TDO_GPIO_Port, &GPIO_InitStruct);

  /*Configure GPIO pins : TDI_Pin TCK_Pin JTAGEN_Pin */
  GPIO_InitStruct.Pin = TDI_Pin|TCK_Pin|JTAGEN_Pin;
  GPIO_InitStruct.Mode = GPIO_MODE_OUTPUT_PP;
  GPIO_InitStruct.Pull = GPIO_NOPULL;
  GPIO_InitStruct.Speed = GPIO_SPEED_FREQ_HIGH;
  HAL_GPIO_Init(GPIOA, &GPIO_InitStruct);

  /*Configure GPIO pins : TMS_Pin MCU_LED_Pin */
  GPIO_InitStruct.Pin = TMS_Pin|MCU_LED_Pin;
  GPIO_InitStruct.Mode = GPIO_MODE_OUTPUT_PP;
  GPIO_InitStruct.Pull = GPIO_NOPULL;
  GPIO_InitStruct.Speed = GPIO_SPEED_FREQ_LOW;
  HAL_GPIO_Init(GPIOA, &GPIO_InitStruct);

  /*Configure GPIO pin : PB2 */
  GPIO_InitStruct.Pin = GPIO_PIN_2;
  GPIO_InitStruct.Mode = GPIO_MODE_OUTPUT_PP;
  GPIO_InitStruct.Pull = GPIO_NOPULL;
  GPIO_InitStruct.Speed = GPIO_SPEED_FREQ_LOW;
  HAL_GPIO_Init(GPIOB, &GPIO_InitStruct);

  /*Configure GPIO pin : PE10 */
  GPIO_InitStruct.Pin = GPIO_PIN_10;
  GPIO_InitStruct.Mode = GPIO_MODE_ANALOG;
  GPIO_InitStruct.Pull = GPIO_NOPULL;
  HAL_GPIO_Init(GPIOE, &GPIO_InitStruct);

  /*Configure GPIO pin : PHY_RST_N_Pin */
  GPIO_InitStruct.Pin = PHY_RST_N_Pin;
  GPIO_InitStruct.Mode = GPIO_MODE_OUTPUT_PP;
  GPIO_InitStruct.Pull = GPIO_PULLDOWN;
  GPIO_InitStruct.Speed = GPIO_SPEED_FREQ_LOW;
  HAL_GPIO_Init(PHY_RST_N_GPIO_Port, &GPIO_InitStruct);

  /*Configure GPIO pin : WS2812B_DI_Pin */
  GPIO_InitStruct.Pin = WS2812B_DI_Pin;
  GPIO_InitStruct.Mode = GPIO_MODE_OUTPUT_PP;
  GPIO_InitStruct.Pull = GPIO_NOPULL;
  GPIO_InitStruct.Speed = GPIO_SPEED_FREQ_HIGH;
  HAL_GPIO_Init(WS2812B_DI_GPIO_Port, &GPIO_InitStruct);

}

/* USER CODE BEGIN 4 */

void sleep_ms(int ms)
{
  HAL_Delay(ms);
}

//****************************************************************************

volatile unsigned int *DWT_CYCCNT   = (volatile unsigned int *)0xE0001004;
volatile unsigned int *DWT_CONTROL  = (volatile unsigned int *)0xE0001000;
volatile unsigned int *DWT_LAR      = (volatile unsigned int *)0xE0001FB0;
volatile unsigned int *SCB_DHCSR    = (volatile unsigned int *)0xE000EDF0;
volatile unsigned int *SCB_DEMCR    = (volatile unsigned int *)0xE000EDFC;
volatile unsigned int *ITM_TER      = (volatile unsigned int *)0xE0000E00;
volatile unsigned int *ITM_TCR      = (volatile unsigned int *)0xE0000E80;

//****************************************************************************

// static int Debug_ITMDebug = 0;

//****************************************************************************

void dwt_enable(void)
{
  // if ((*SCB_DHCSR & 1) && (*ITM_TER & 1)) // Enabled?
  //   Debug_ITMDebug = 1;

  *SCB_DEMCR |= 0x01000000;
  *DWT_LAR = 0xC5ACCE55; // enable access
  *DWT_CYCCNT = 0; // reset the counter
  *DWT_CONTROL |= 1 ; // enable the counter
}

//****************************************************************************

void cpu_delay(uint32_t cycles)
{
  *DWT_CYCCNT = 0; // reset the counter
  while((*DWT_CYCCNT) < cycles);
}

void delay_x100ns_at_400MHz_CPU(int n)
{
  // a nop 2.5ns
  int i = 0;
  for (i = 0; i < 10 * n; i++) {
    __NOP();
    __NOP();
    __NOP();
    __NOP();
  }
}

// h=1000ns, l=500ns
void ws2812b_write_h()
{
  HAL_GPIO_WritePin(WS2812B_DI_GPIO_Port, WS2812B_DI_Pin, GPIO_PIN_SET);
  delay_x100ns_at_400MHz_CPU(10); // 1us
  HAL_GPIO_WritePin(WS2812B_DI_GPIO_Port, WS2812B_DI_Pin, GPIO_PIN_RESET);
  delay_x100ns_at_400MHz_CPU(5); // 0.5us
}

// h=200ns, l=1300ns
void ws2812b_write_l()
{
  HAL_GPIO_WritePin(WS2812B_DI_GPIO_Port, WS2812B_DI_Pin, GPIO_PIN_SET);
  delay_x100ns_at_400MHz_CPU(2); // 0.1us
  HAL_GPIO_WritePin(WS2812B_DI_GPIO_Port, WS2812B_DI_Pin, GPIO_PIN_RESET);
  delay_x100ns_at_400MHz_CPU(13); // 1.3us
}

// this function is busy
// it will disable global interrupt
// function call about 1.5*24 = 36us
// TODO: change this to a aysnc function
void ws2812b_set_color(uint8_t red, uint8_t green, uint8_t blue)
{
  __disable_irq();

  // g, r, b
  int i;
  for (i = 0; i < 8; i++) {
    if (green & 0x80) {
      ws2812b_write_h();
    } else {
      ws2812b_write_l();
    }
    green = green << 1;
  }

  for (i = 0; i < 8; i++) {
    if (red & 0x80) {
      ws2812b_write_h();
    } else {
      ws2812b_write_l();
    }
    red = red << 1;
  }

  for (i = 0; i < 8; i++) {
    if (blue & 0x80) {
      ws2812b_write_h();
    } else {
      ws2812b_write_l();
    }
    blue = blue << 1;
  }

  __enable_irq();
}

int adc1_get_voltage_mv(uint32_t channel, uint16_t *mv)
{
  ADC_ChannelConfTypeDef sConfig = {0};

  sConfig.Channel = channel;
  sConfig.Rank = ADC_REGULAR_RANK_1;
  sConfig.SamplingTime = ADC_SAMPLETIME_64CYCLES_5;
  sConfig.SingleDiff = ADC_SINGLE_ENDED;
  sConfig.OffsetNumber = ADC_OFFSET_NONE;
  sConfig.Offset = 0;
  sConfig.OffsetSignedSaturation = DISABLE;
  if (HAL_ADC_ConfigChannel(&hadc1, &sConfig) != HAL_OK) {
    ctrace("adc1 config ch%d fail\n", channel);
    return -1;
  }
  uint32_t rawv = 0;
  HAL_ADC_Start(&hadc1);
  if (HAL_ADC_PollForConversion(&hadc1, 10) != HAL_OK) {
    ctrace("adc1 poll ch%d fail\n", channel);
    return -2;
  }
  rawv = HAL_ADC_GetValue(&hadc1);
  rawv = rawv / ADC1_OVERSAMPLING_RATIO;
  *mv = (((rawv * ADC1_VREF_VOLTAGE) / (65535)));

  return 0;
}

/**
 * usb cdc interface 0 is cli interface, ex: ttyACM0
 * usb cdc interface 1 is raw cmd interface, ex: ttyACM1
 */

static void cdc_task(void)
{
  // uint8_t itf;
  // static uint8_t buf[1024];
  // int i;

  // for (itf = 0; itf < CFG_TUD_CDC; itf++) {
  //   // connected() check for DTR bit
  //   // Most but not all terminal client set this when making connection
  //   // if ( tud_cdc_n_connected(itf) )
  //   {
  //     if (tud_cdc_n_available(itf)) {
  //       uint32_t count = tud_cdc_n_read(itf, buf, sizeof(buf));
  //       // if (buf[0] == 'e') {
  //       //   for (i = 0; i < 1000000; i++) {
  //       //     tud_cdc_n_write(itf, buf, 1024);
  //       //     tud_cdc_n_write_flush(itf);
  //       //     tud_task();
  //       //   }
  //       // }
  //       tud_cdc_n_write(itf, buf, count);
  //       tud_cdc_n_write_flush(itf);
  //     }
  //   }
  // }

  // static uint8_t buf[128];
  // int i;

  // if ( tud_cdc_n_connected(0) ){
  //   if (tud_cdc_n_available(0)) {
  //     uint32_t count = tud_cdc_n_read(0, buf, sizeof(buf));
  //     if(count > 0){
  //     }
  //   }
  // }
}

void StartUsbTask(void *argument)
{
  vTaskDelay(portTICK_PERIOD_MS * 2000);
  tud_init(BOARD_TUD_RHPORT);

  for (;;) {
    tud_task(); // tinyusb device task
    cdc_task();
  }
}

void StartCliTask(void *argument)
{
  int ret;

  // enable cli console
  console_init(usb_get_char, usb_put_char, usb_put_buf, (f_get_tick_ms)get_tick_ms);
  // console_init(uart_get_char, uart_put_char, uart_put_buf, (f_get_tick_ms)get_tick_ms);
  console_set_log_level(LOG_INFO);

  char *cmd = NULL;
  for (;;) {
    osDelay(100);
    cmd = check_command();
    if (cmd) {
      ret = pico_process_cmd(cmd);
      if (ret != 255) {
        if (ret == 0) {
          cprintf("\n$PASS$\n");
        } else {
          cprintf("\nERRCODE: %d\n", ret);
          cprintf("\n$FAIL$\n");
        }
      }
      cprintf("$>");
    }
  }
}

void StartiWDGTask(void *argument)
{
  for (;;) {
    vTaskDelay(portTICK_PERIOD_MS*100);
    HAL_IWDG_Refresh(&hiwdg1);
  }
}

/* USER CODE END 4 */

void StartDefaultTask(void *argument)
{
  /* init code for LWIP */
  MX_LWIP_Init();
  /* USER CODE BEGIN 5 */
  uint16_t v;

  iwdgTaskHandle = osThreadNew(StartiWDGTask, NULL, &iwdgTask_attributes);
  usbTaskHandle = osThreadNew(StartUsbTask, NULL, &usbTask_attributes);
  cliTaskHandle = osThreadNew(StartCliTask, NULL, &cliTask_attributes);

  dwt_enable();

  /* Infinite loop */
  for(;;)
  {
    vTaskDelay(portTICK_PERIOD_MS*g_heat_led_gap);
    HAL_GPIO_WritePin(MCU_LED_GPIO_Port, MCU_LED_Pin, GPIO_PIN_SET);
    // ws2812b_set_color(10, 0, 0);
    vTaskDelay(portTICK_PERIOD_MS*g_heat_led_gap);
    HAL_GPIO_WritePin(MCU_LED_GPIO_Port, MCU_LED_Pin, GPIO_PIN_RESET);
    // ws2812b_set_color(0, 10, 0);

    if (0 == adc1_get_voltage_mv(POUT_ADC_CH, &v)) {
      pico_reg.voltage._.pout = v;
    }

    if (0 == adc1_get_voltage_mv(PLD_VREF_ADC_CH, &v)) {
      pico_reg.voltage._.vref = v;
    }
  }
  /* USER CODE END 5 */
}

/* MPU Configuration */

void MPU_Config(void)
{
  MPU_Region_InitTypeDef MPU_InitStruct = {0};

  /* Disables the MPU */
  HAL_MPU_Disable();
  /** Initializes and configures the Region and the memory to be protected
  */
  MPU_InitStruct.Enable = MPU_REGION_ENABLE;
  MPU_InitStruct.Number = MPU_REGION_NUMBER0;
  MPU_InitStruct.BaseAddress = 0x30000000;
  MPU_InitStruct.Size = MPU_REGION_SIZE_32KB;
  MPU_InitStruct.SubRegionDisable = 0x0;
  MPU_InitStruct.TypeExtField = MPU_TEX_LEVEL1;
  MPU_InitStruct.AccessPermission = MPU_REGION_FULL_ACCESS;
  MPU_InitStruct.DisableExec = MPU_INSTRUCTION_ACCESS_DISABLE;
  MPU_InitStruct.IsShareable = MPU_ACCESS_NOT_SHAREABLE;
  MPU_InitStruct.IsCacheable = MPU_ACCESS_NOT_CACHEABLE;
  MPU_InitStruct.IsBufferable = MPU_ACCESS_NOT_BUFFERABLE;

  HAL_MPU_ConfigRegion(&MPU_InitStruct);
  /** Initializes and configures the Region and the memory to be protected
  */
  MPU_InitStruct.Number = MPU_REGION_NUMBER1;
  MPU_InitStruct.Size = MPU_REGION_SIZE_512B;
  MPU_InitStruct.TypeExtField = MPU_TEX_LEVEL0;
  MPU_InitStruct.IsShareable = MPU_ACCESS_SHAREABLE;
  MPU_InitStruct.IsBufferable = MPU_ACCESS_BUFFERABLE;

  HAL_MPU_ConfigRegion(&MPU_InitStruct);
  /* Enables the MPU */
  HAL_MPU_Enable(MPU_PRIVILEGED_DEFAULT);

}

void HAL_TIM_PeriodElapsedCallback(TIM_HandleTypeDef *htim)
{
  if (htim->Instance == TIM2) {
    HAL_IncTick();
  }
}

void Error_Handler(void)
{
  __disable_irq();
  while (1)
  {
  }
}
